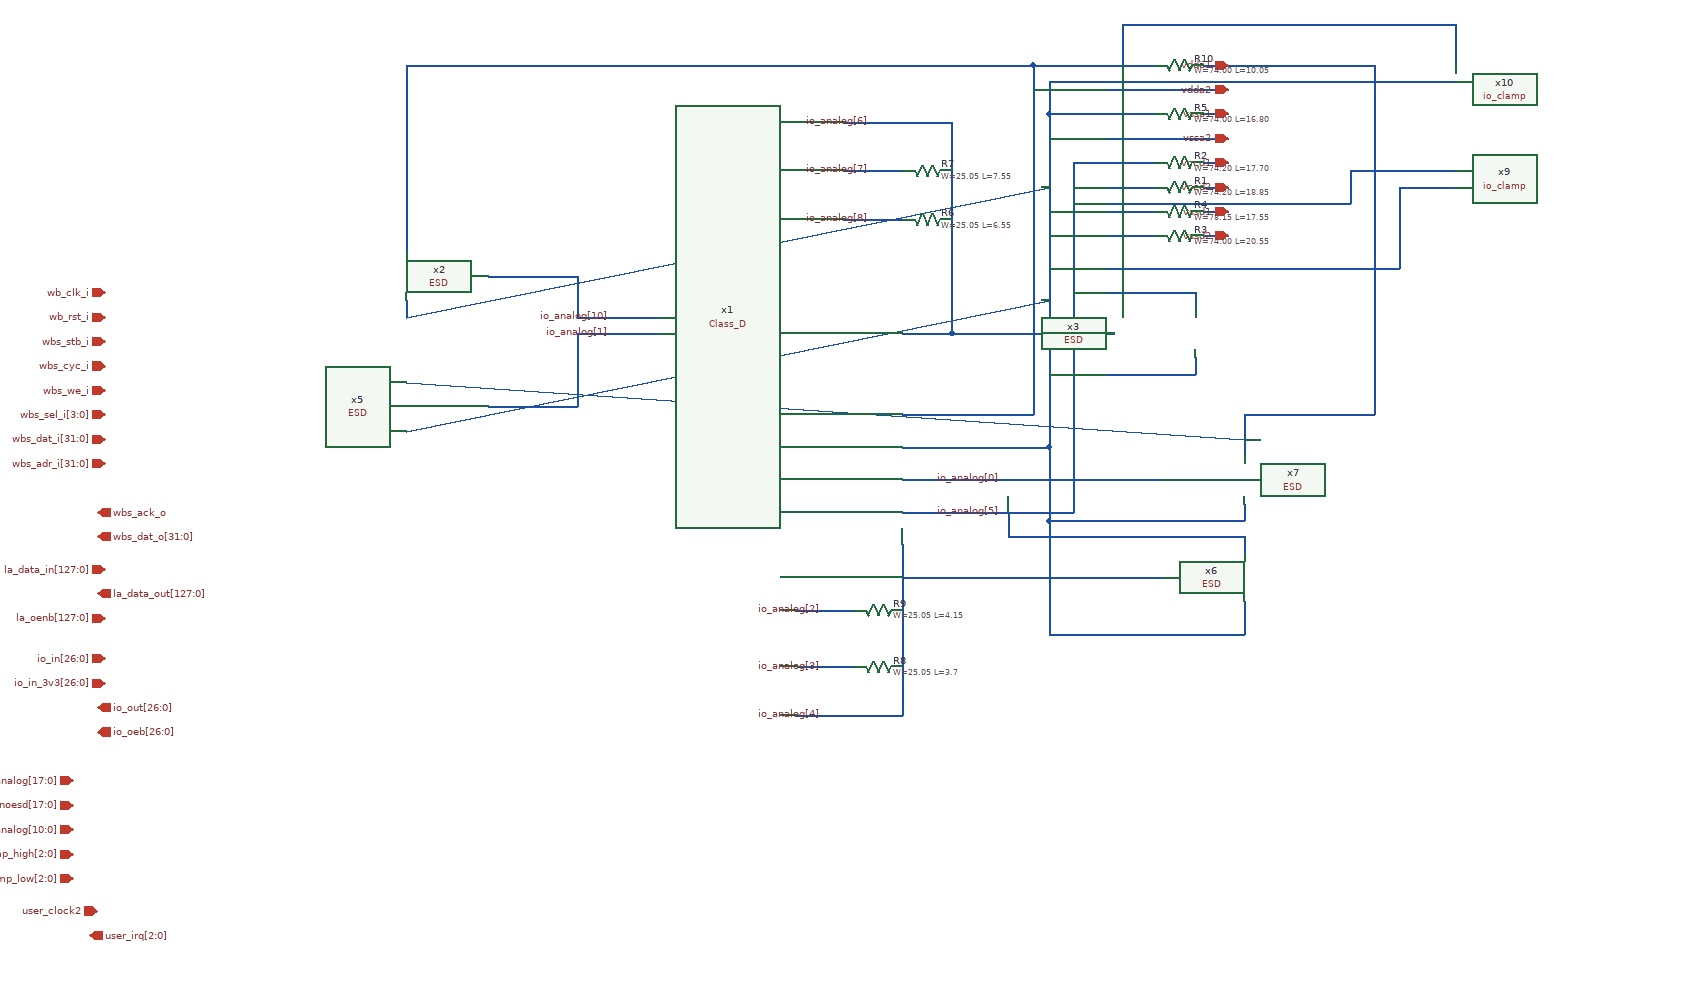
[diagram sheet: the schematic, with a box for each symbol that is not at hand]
v {xschem version=2.9.9 file_version=1.2 }
G {}
K {}
V {}
S {}
E {}
N 4300 190 4370 190 { lab=io_analog[2]}
N 4300 260 4370 260 { lab=io_analog[3]}
N 4300 320 4370 320 { lab=io_analog[4]}
N 4360 -410 4430 -410 { lab=io_analog[6]}
N 4360 -350 4430 -350 { lab=io_analog[7]}
N 4360 -290 4430 -290 { lab=io_analog[8]}
N 4800 -330 4830 -330 { lab=vccd2}
N 4800 -360 4830 -360 { lab=vccd1}
N 4800 -270 4830 -270 { lab=vssd2}
N 4800 -300 4830 -300 { lab=vssd1}
N 4800 -420 4830 -420 { lab=vssa1}
N 4430 70 4510 70 { lab=io_analog[5]}
N 4510 70 4640 70 { lab=io_analog[5]}
N 4640 -360 4640 70 { lab=io_analog[5]}
N 4640 -360 4740 -360 { lab=io_analog[5]}
N 4640 -330 4740 -330 { lab=io_analog[5]}
N 4610 -420 4740 -420 { lab=vssa2}
N 4610 -270 4740 -270 { lab=vssa2}
N 4610 -300 4740 -300 { lab=vssa2}
N 4610 -390 4830 -390 { lab=vssa2}
N 4610 -420 4610 -210 { lab=vssa2}
N 4610 -210 4610 -10 { lab=vssa2}
N 4430 -10 4610 -10 { lab=vssa2}
N 4430 -150 4490 -150 { lab=io_analog[6]}
N 4490 -410 4490 -150 { lab=io_analog[6]}
N 4430 -410 4490 -410 { lab=io_analog[6]}
N 4430 110 4430 320 { lab=io_analog[4]}
N 4370 320 4430 320 { lab=io_analog[4]}
N 4030 -170 4130 -170 { lab=io_analog[10]}
N 4030 -150 4130 -150 { lab=io_analog[1]}
N 4430 30 4520 30 { lab=io_analog[0]}
N 4520 30 4750 30 { lab=io_analog[0]}
N 4430 150 4750 150 { lab=io_analog[4]}
N 4490 -150 4690 -150 { lab=io_analog[6]}
N 3920 -220 4030 -220 { lab=io_analog[10]}
N 4030 -220 4030 -170 { lab=io_analog[10]}
N 3920 -60 4030 -60 { lab=io_analog[1]}
N 4030 -150 4030 -60 { lab=io_analog[1]}
N 4640 -310 4980 -310 { lab=io_analog[5]}
N 4980 -350 4980 -310 { lab=io_analog[5]}
N 4980 -350 5110 -350 { lab=io_analog[5]}
N 5040 -330 5110 -330 { lab=vssa2}
N 5040 -330 5040 -230 { lab=vssa2}
N 4610 -230 5040 -230 { lab=vssa2}
N 4610 -460 5110 -460 { lab=vssa2}
N 4610 -460 4610 -420 { lab=vssa2}
N 4800 -480 4830 -480 { lab=vdda1}
N 4590 -450 4830 -450 { lab=vdda2}
N 4590 -480 4740 -480 { lab=vdda2}
N 4590 -480 4590 -50 { lab=vdda2}
N 4430 -50 4590 -50 { lab=vdda2}
N 4790 -200 4790 -180 { lab=io_analog[5]}
N 4640 -200 4790 -200 { lab=io_analog[5]}
N 4790 -120 4790 -100 { lab=vssa2}
N 4610 -100 4790 -100 { lab=vssa2}
N 4850 -50 4850 -0 { lab=vdda1}
N 4850 -50 5010 -50 { lab=vdda1}
N 5010 -480 5010 -50 { lab=vdda1}
N 4850 60 4850 80 { lab=vssa2}
N 4610 80 4850 80 { lab=vssa2}
N 4610 -10 4610 80 { lab=vssa2}
N 4850 180 4850 220 { lab=vssa2}
N 4610 220 4850 220 { lab=vssa2}
N 4610 80 4610 220 { lab=vssa2}
N 4850 100 4850 120 { lab=io_analog[5]}
N 4560 100 4850 100 { lab=io_analog[5]}
N 4560 70 4560 100 { lab=io_analog[5]}
N 3820 -480 3820 -250 { lab=vdda2}
N 3820 -480 4590 -480 { lab=vdda2}
N 3820 -190 3820 -170 { lab=vssa2}
N 3820 -170 4610 -330 { lab=vssa2}
N 3820 -90 4850 -20 { lab=vdda1}
N 3820 -30 4610 -190 { lab=vssa2}
N 4830 -480 5010 -480 { lab=vdda1}
N 5110 -530 5110 -480 { lab=vdda2}
N 4700 -530 5110 -530 { lab=vdda2}
N 4700 -530 4700 -480 { lab=vdda2}
C {iopin.sym} 4830 -480 0 0 {name=p1 lab=vdda1}
C {iopin.sym} 4830 -450 0 0 {name=p2 lab=vdda2}
C {iopin.sym} 4830 -420 0 0 {name=p3 lab=vssa1}
C {iopin.sym} 4830 -390 0 0 {name=p4 lab=vssa2}
C {iopin.sym} 4830 -360 0 0 {name=p5 lab=vccd1}
C {iopin.sym} 4830 -330 0 0 {name=p6 lab=vccd2}
C {iopin.sym} 4830 -300 0 0 {name=p7 lab=vssd1}
C {iopin.sym} 4830 -270 0 0 {name=p8 lab=vssd2}
C {ipin.sym} 3450 -200 0 0 {name=p9 lab=wb_clk_i}
C {ipin.sym} 3450 -170 0 0 {name=p10 lab=wb_rst_i}
C {ipin.sym} 3450 -140 0 0 {name=p11 lab=wbs_stb_i}
C {ipin.sym} 3450 -110 0 0 {name=p12 lab=wbs_cyc_i}
C {ipin.sym} 3450 -80 0 0 {name=p13 lab=wbs_we_i}
C {ipin.sym} 3450 -50 0 0 {name=p14 lab=wbs_sel_i[3:0]}
C {ipin.sym} 3450 -20 0 0 {name=p15 lab=wbs_dat_i[31:0]}
C {ipin.sym} 3450 10 0 0 {name=p16 lab=wbs_adr_i[31:0]}
C {opin.sym} 3440 70 0 0 {name=p17 lab=wbs_ack_o}
C {opin.sym} 3440 100 0 0 {name=p18 lab=wbs_dat_o[31:0]}
C {ipin.sym} 3450 140 0 0 {name=p19 lab=la_data_in[127:0]}
C {opin.sym} 3440 170 0 0 {name=p20 lab=la_data_out[127:0]}
C {ipin.sym} 3450 250 0 0 {name=p21 lab=io_in[26:0]}
C {ipin.sym} 3450 280 0 0 {name=p22 lab=io_in_3v3[26:0]}
C {ipin.sym} 3440 560 0 0 {name=p23 lab=user_clock2}
C {opin.sym} 3440 310 0 0 {name=p24 lab=io_out[26:0]}
C {opin.sym} 3440 340 0 0 {name=p25 lab=io_oeb[26:0]}
C {iopin.sym} 3410 400 0 0 {name=p26 lab=gpio_analog[17:0]}
C {iopin.sym} 3410 430 0 0 {name=p27 lab=gpio_noesd[17:0]}
C {iopin.sym} 3410 460 0 0 {name=p29 lab=io_analog[10:0]}
C {iopin.sym} 3410 490 0 0 {name=p30 lab=io_clamp_high[2:0]}
C {iopin.sym} 3410 520 0 0 {name=p31 lab=io_clamp_low[2:0]}
C {opin.sym} 3430 590 0 0 {name=p32 lab=user_irq[2:0]}
C {ipin.sym} 3450 200 0 0 {name=p28 lab=la_oenb[127:0]}
C {src/Class_D/Class_D.sym} 4280 -30 0 0 {name=x1}
C {src/ESD/ESD.sym} 3870 -220 0 0 {name=x2}
C {src/ESD/ESD.sym} 3870 -60 0 0 {name=x5}
C {src/ESD/ESD.sym} 4800 150 0 1 {name=x6}
C {src/ESD/io_clamp.sym} 5260 -340 0 1 {name=x9}
C {src/ESD/io_clamp.sym} 5260 -470 0 1 {name=x10}
C {src/ESD/ESD.sym} 4740 -150 0 1 {name=x3}
C {src/ESD/ESD.sym} 4800 30 0 1 {name=x7}
C {lab_wire.sym} 4330 190 0 0 {name=l14 sig_type=std_logic lab=io_analog[2]}
C {lab_wire.sym} 4330 260 0 0 {name=l20 sig_type=std_logic lab=io_analog[3]}
C {lab_wire.sym} 4330 320 0 0 {name=l21 sig_type=std_logic lab=io_analog[4]}
C {lab_wire.sym} 4390 -410 0 0 {name=l22 sig_type=std_logic lab=io_analog[6]}
C {lab_wire.sym} 4390 -350 0 0 {name=l23 sig_type=std_logic lab=io_analog[7]}
C {lab_wire.sym} 4390 -290 0 0 {name=l24 sig_type=std_logic lab=io_analog[8]}
C {sky130_fd_pr/res_generic_m1.sym} 4770 -330 3 1 {name=R1
W=74.20
L=18.85
model=res_generic_m5
spiceprefix=X
mult=1}
C {sky130_fd_pr/res_generic_m1.sym} 4770 -360 3 1 {name=R2
W=74.20
L=17.70
model=res_generic_m5
spiceprefix=X
mult=1}
C {sky130_fd_pr/res_generic_m1.sym} 4770 -270 3 1 {name=R3
W=74.00
L=20.55
model=res_generic_m3
spiceprefix=X
mult=1}
C {sky130_fd_pr/res_generic_m1.sym} 4770 -300 3 1 {name=R4
W=78.15
L=17.55
model=res_generic_m4
spiceprefix=X
mult=1}
C {sky130_fd_pr/res_generic_m1.sym} 4770 -420 3 1 {name=R5
W=74.00
L=16.80
model=res_generic_m4
spiceprefix=X
mult=1}
C {sky130_fd_pr/res_generic_m1.sym} 4460 -290 3 1 {name=R6
W=25.05
L=6.55
model=res_generic_m3
spiceprefix=X
mult=1}
C {sky130_fd_pr/res_generic_m1.sym} 4460 -350 3 1 {name=R7
W=25.05
L=7.55
model=res_generic_m3
spiceprefix=X
mult=1}
C {sky130_fd_pr/res_generic_m1.sym} 4400 260 3 1 {name=R8
W=25.05
L=3.7
model=res_generic_m3
spiceprefix=X
mult=1}
C {sky130_fd_pr/res_generic_m1.sym} 4400 190 3 1 {name=R9
W=25.05
L=4.15
model=res_generic_m3
spiceprefix=X
mult=1}
C {lab_wire.sym} 4470 70 0 1 {name=l1 sig_type=std_logic lab=io_analog[5]}
C {lab_wire.sym} 4070 -170 0 0 {name=l2 sig_type=std_logic lab=io_analog[10]}
C {lab_wire.sym} 4070 -150 0 0 {name=l3 sig_type=std_logic lab=io_analog[1]}
C {lab_wire.sym} 4470 30 0 1 {name=l4 sig_type=std_logic lab=io_analog[0]}
C {sky130_fd_pr/res_generic_m1.sym} 4770 -480 3 1 {name=R10
W=74.00
L=10.05
model=res_generic_m5
spiceprefix=X
mult=1}
